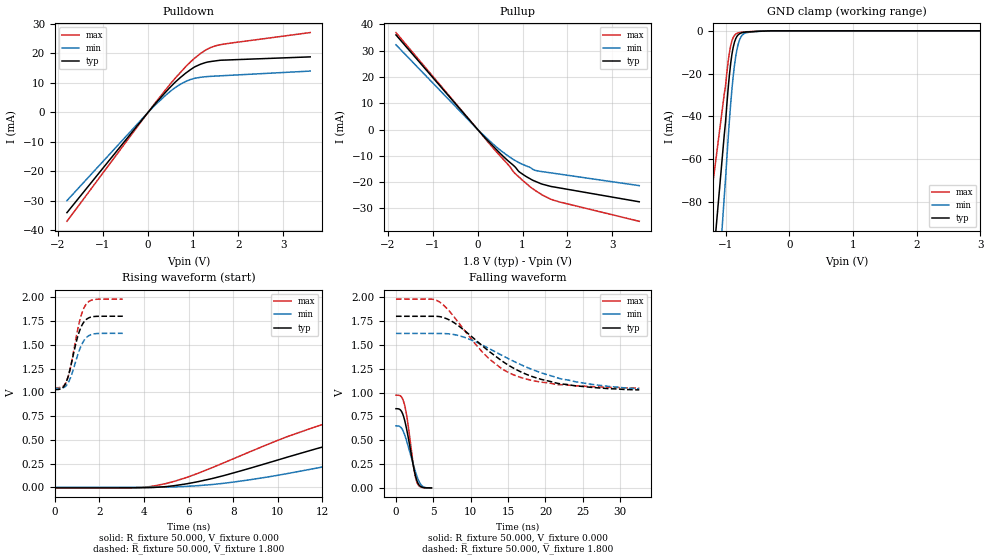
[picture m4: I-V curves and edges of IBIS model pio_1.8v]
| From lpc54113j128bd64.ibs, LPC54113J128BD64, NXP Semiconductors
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[Model]   pio_1.8v
Model_type I/O
Vinl=4.000E-01
Vinh=1.500E+00
Vref=0.000E+00
Rref=1.000E+06
Cref=2.000E-11
Vmeas=9.000E-01
C_comp   9.060E-12   8.700E-12   9.420E-12
[Voltage Range]   1.800E+00   1.620E+00   1.980E+00
[POWER Clamp Reference]   1.800E+00   1.620E+00   1.980E+00
[GND Clamp Reference]   0.000E+00   0.000E+00   0.000E+00
[Pullup Reference]   1.800E+00   1.620E+00   1.980E+00
[Pulldown Reference]   0.000E+00   0.000E+00   0.000E+00
[Temperature Range]   25   105   -40
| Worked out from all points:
|   slope of the pulldown table from 0 to 0.27 V, typ, clamps not added: 55.9 ohm
|   slope of the pullup table from 0 to 0.27 V, typ, clamps not added: 53.5 ohm
|   GND clamp passes 1 mA (typ) near -0.75 V on its own axis
|   rising waveform, R_fixture 50.000, V_fixture 0.000: 20-80 % time 8.49ns typ, 10.2ns min, 6.96ns max; typ from -0.006 V to 0.824 V
|   falling waveform, R_fixture 50.000, V_fixture 0.000: 20-80 % time 1.2ns typ, 1.45ns min, 1.03ns max; typ from 0.831 V to 0 V
|   rising waveform, R_fixture 50.000, V_fixture 1.800: 20-80 % time 492ps typ, 502ps min, 486ps max; typ from 1.03 V to 1.8 V
|   falling waveform, R_fixture 50.000, V_fixture 1.800: 20-80 % time 8.49ns typ, 10.1ns min, 6.71ns max; typ from 1.8 V to 1.03 V
[GND Clamp]
-1.8V     -313.7mA   -417.6mA   -211.3mA
-1.02V    -48.43mA   -77.27mA   -29.38mA
-1V       -42.42mA   -69.05mA   -25.58mA
-960mV    -27.18mA   -50.55mA   -14.48mA
-920mV    -15.31mA   -34.21mA   -6.985mA
-880mV    -7.67mA    -21.17mA   -3.102mA
-860mV    -5.28mA    -16.06mA   -2.117mA
-820mV    -2.521mA   -8.561mA   -1.165mA
-780mV    -1.374mA   -4.216mA   -808.9uA
-720mV    -714.3uA   -1.509mA   -555.8uA
-460mV    -181.7uA   -231.5uA   -147.4uA
3.6V      0A         0A         0A
[Power Clamp]
-1.8V     0A         0A         0A
0V        0A         0A         0A
1.8V      0A         0A         0A
3.6V      0A         0A         0A
[Pullup]
-1.82V    35.96mA    32.21mA    36.85mA
80mV      -1.544mA   -1.344mA   -1.647mA
500mV     -9.045mA   -7.794mA   -9.994mA
700mV     -12.23mA   -10.32mA   -13.77mA
800mV     -13.69mA   -11.44mA   -16.11mA
940mV     -16.27mA   -12.77mA   -18.38mA
1.16V     -18.65mA   -14.36mA   -21.65mA
1.26V     -19.53mA   -15.44mA   -22.89mA
1.44V     -20.77mA   -16.02mA   -24.89mA
1.66V     -21.72mA   -16.55mA   -26.68mA
3.6V      -27.48mA   -21.34mA   -34.89mA
[Pulldown]
-1.8V     -34.01mA   -29.94mA   -36.95mA
0V        0A         0A         0A
380mV     6.716mA    5.665mA    7.485mA
600mV     10.22mA    8.397mA    11.57mA
840mV     13.38mA    10.54mA    15.59mA
1.02V     15.31mA    11.52mA    18.23mA
1.16V     16.32mA    11.92mA    19.92mA
1.38V     17.25mA    12.23mA    21.97mA
1.62V     17.72mA    12.43mA    23.02mA
3.6V      18.85mA    14.03mA    27.1mA
[Rising Waveform]
R_fixture = 50.000
V_fixture = 0.000
V_fixture_min = 0.000
V_fixture_max = 0.000
|  time   V(typ)   V(min)   V(max)
0s        -5.789mV   0V         -4.844mV
3.7ns     -4.923mV   179.8uV    -2.372mV
4.95ns    6.383mV    1.85mV     37.73mV
7.05ns    91.82mV    29.27mV    206.2mV
11.75ns   407.3mV    202.4mV    641.5mV
13.6ns    519.6mV    285mV      761.3mV
15.5ns    613.2mV    364.1mV    841.4mV
20.9ns    764.1mV    536.8mV    935mV
25.8ns    810.2mV    620.8mV    959mV
30.1ns    823.9mV    650.4mV    967.2mV
[Falling Waveform]
R_fixture = 50.000
V_fixture = 0.000
V_fixture_min = 0.000
V_fixture_max = 0.000
|  time   V(typ)   V(min)   V(max)
0s        830.6mV    650.4mV    972mV
650ps     812.3mV    635.1mV    961.1mV
900ps     775.6mV    605.9mV    931.4mV
1.15ns    712.7mV    559.4mV    870.2mV
1.6ns     546.5mV    445mV      672.5mV
2.4ns     200.9mV    223.8mV    201.5mV
2.8ns     75.51mV    123mV      59.46mV
3.1ns     28.6mV     65.27mV    20.05mV
3.55ns    5.81mV     17.39mV    3.696mV
4.75ns    0V         0V         0V
[Rising Waveform]
R_fixture = 50.000
V_fixture = 1.800
V_fixture_min = 1.620
V_fixture_max = 1.980
|  time   V(typ)   V(min)   V(max)
0s        1.028V     1.04V      1.048V
350ps     1.047V     1.046V     1.059V
550ps     1.131V     1.081V     1.128V
700ps     1.257V     1.15V      1.256V
1.05ns    1.603V     1.408V     1.686V
1.2ns     1.697V     1.498V     1.821V
1.4ns     1.764V     1.571V     1.924V
1.55ns    1.786V     1.598V     1.958V
1.75ns    1.797V     1.614V     1.975V
3.05ns    1.8V       1.62V      1.98V
[Falling Waveform]
R_fixture = 50.000
V_fixture = 1.800
V_fixture_min = 1.620
V_fixture_max = 1.980
|  time   V(typ)   V(min)   V(max)
0s        1.8V       1.62V      1.98V
4.75ns    1.8V       1.62V      1.98V
5.8ns     1.797V     1.619V     1.952V
8.15ns    1.713V     1.602V     1.756V
12.3ns    1.442V     1.468V     1.366V
14.15ns   1.333V     1.391V     1.25V
16.25ns   1.234V     1.309V     1.17V
21.75ns   1.095V     1.151V     1.083V
26.55ns   1.052V     1.082V     1.061V
32.55ns   1.028V     1.04V      1.048V
[Ramp]
dV/dt_r   4.9781E-01/8.4744E-09   3.9098E-01/1.0185E-08   5.8325E-01/6.9452E-09
dV/dt_f   4.6327E-01/8.4811E-09   3.4800E-01/1.0136E-08   5.5946E-01/6.7072E-09
R_load = 50
